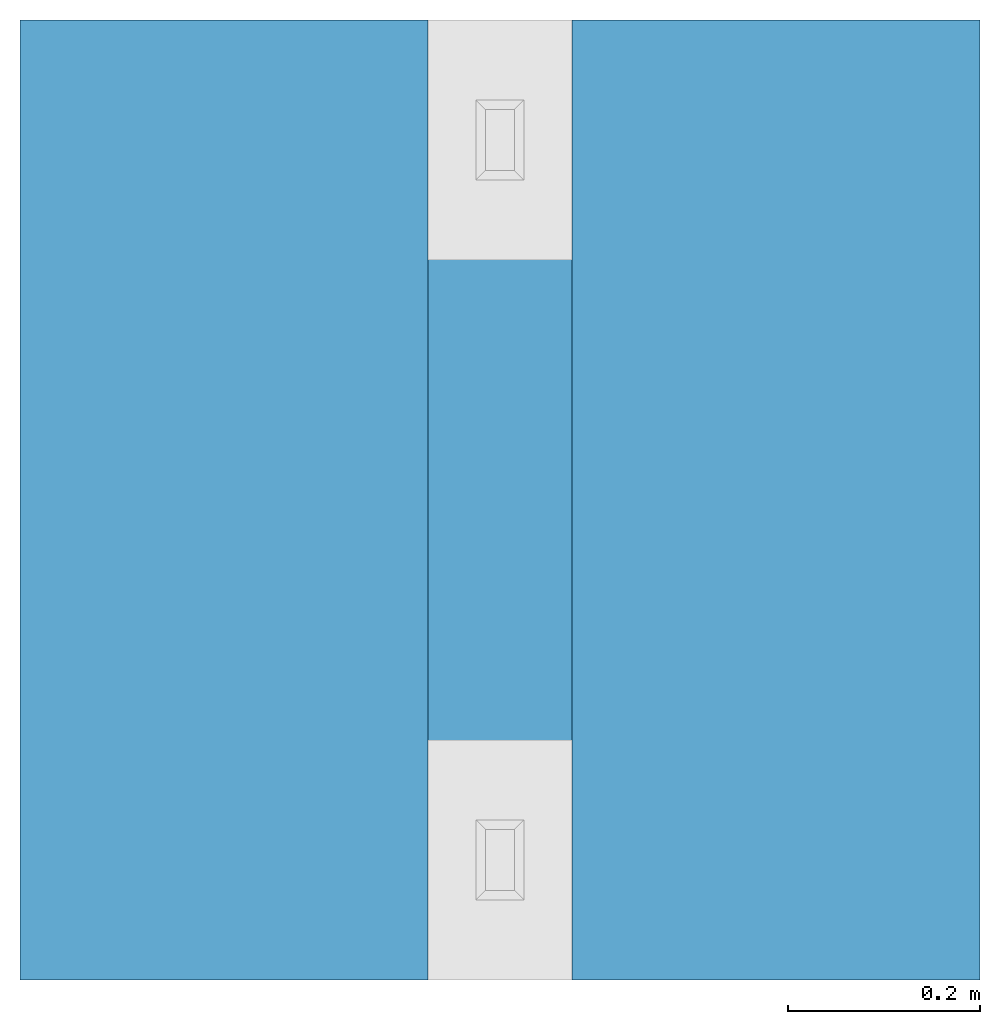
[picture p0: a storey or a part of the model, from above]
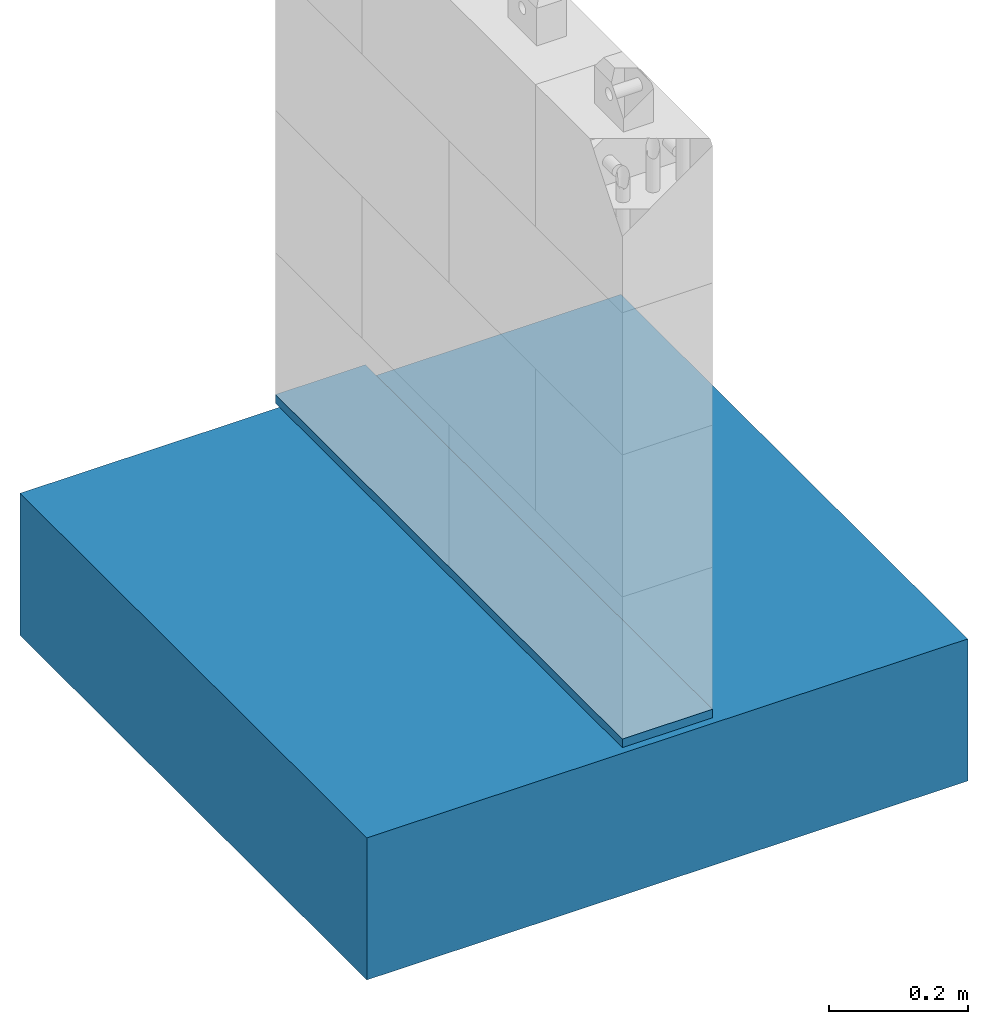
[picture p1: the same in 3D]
Properties of the parts of a building model (IFC4)

# File
Description: ViewDefinition [ReferenceView_V1.2], RevitIdentifiers [VersionGUID: 7834f85f-64b1-4d97-9455-e0bbda0907ea, NumberOfSaves: 6], CoordinateReference [CoordinateBase: Internal Origin, ProjectSite: Internal], ExchangeRequirement [Architecture]
Time: 2025-04-04T17:46:37+01:00
Written by: ODA SDAI 24.6
Made in: Autodesk Revit 24.2.10.64 (ENU) - IFC 24.2.0.49

# IfcSite, Default
RefLatitude: 45, 45, 37, 23925; RefLongitude: 21, 14, 26, 780090; RefElevation: 0 cm

# IfcBuildingStorey: Level:ABOVE SLAB__Symbols Both Ends (10)
Name | LongName | Elevation (cm)
B2__ABOVE Slab | B2__ABOVE Slab | -612
B1__ABOVE Slab | B1__ABOVE Slab | -312
L00__ABOVE Slab | L00__ABOVE Slab | -12
L01__ABOVE Slab | L01__ABOVE Slab | 273
L02__ABOVE Slab | L02__ABOVE Slab | 558
L03__ABOVE Slab | L03__ABOVE Slab | 843
L04__ABOVE Slab | L04__ABOVE Slab | 1128
L05__ABOVE Slab | L05__ABOVE Slab | 1413
L06__ABOVE Slab | L06__ABOVE Slab | 1698
L07__ABOVE Slab | L07__ABOVE Slab | 1983

# IfcBeam: Structural Framing : Light Gauge-Angles : L150 x 150 (4)
In: L02__ABOVE Slab
Type - PredefinedType: BEAM; Material: Metal - Steel - 345 MPa
Classification: B10 Uniformat (Uniformat)

# IfcBeam: Structural Framing : sfr__WOOD__Rectangular__sf : 15 x 1cm
In: L00__ABOVE Slab
Type - PredefinedType: BEAM; Material: _STRUCTURE__Wood
Classification: III-3 Uniformat (Uniformat)

# IfcBuildingElementPart, _STRUCTURE__Reinforced Concrete
In: L00__ABOVE Slab
Material: _STRUCTURE__Reinforced Concrete

# IfcColumn: Columns : wll__TIMBER CORE__Triqbriq__lb : WS15
In: L00__ABOVE Slab
Type - PredefinedType: COLUMN; Material: <Unnamed>

# IfcColumn: Columns : wll_s__TIMBER BLOCK__Triqbriq, Full Width__wp : WS15 (6)
In: L00__ABOVE Slab
Type - PredefinedType: COLUMN; Material: _MASONRY__Timber Block__Triqbriq, X, _MASONRY__Timber Block__Triqbriq, Y

# IfcColumn: Columns : wll_s__TIMBER BLOCK__Triqbriq, Half Width__wp : WS15 (4)
In: L00__ABOVE Slab
Type - PredefinedType: COLUMN; Material: _MASONRY__Timber Block__Triqbriq, X, _MASONRY__Timber Block__Triqbriq, Y

# IfcSlab: Floors : Floor : flr__STRUCTURE__Reinforced Concrete 25cm
In: L00__ABOVE Slab
Type - PredefinedType: FLOOR
Classification: S 1.2 Uniformat (Uniformat)
